One B-rep face of a CAD part: STEP entity #139.
In plain terms, the planar face has unit normal (-1, 0, 0).
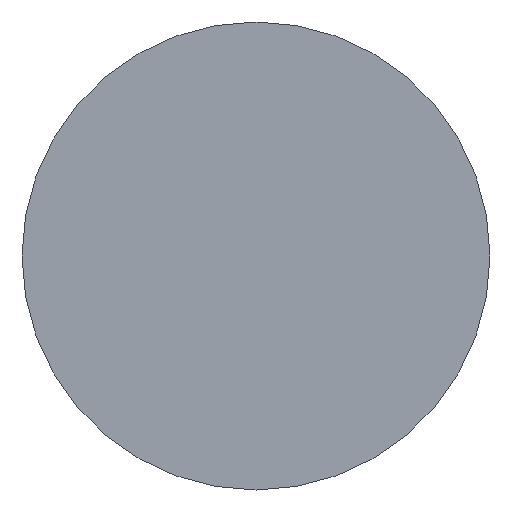
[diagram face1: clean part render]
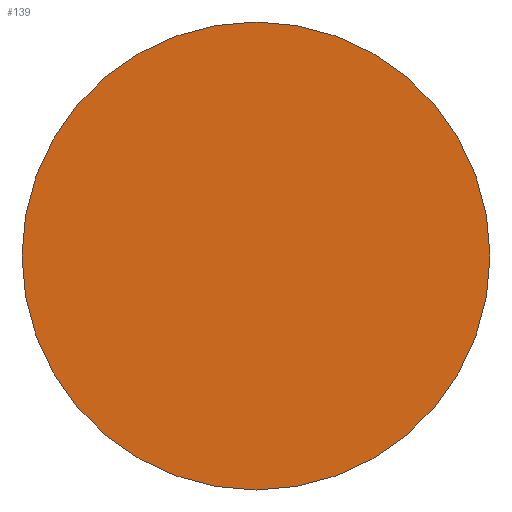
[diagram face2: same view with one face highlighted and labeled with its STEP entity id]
Its self-contained STEP definition (entity closure, numbers rounded to 3 decimals):
#31 = CYLINDRICAL_SURFACE('',#32,1.9);
#32 = AXIS2_PLACEMENT_3D('',#33,#34,#35);
#33 = CARTESIAN_POINT('',(-43.1,28.,239.));
#34 = DIRECTION('',(1.,0.,0.));
#35 = DIRECTION('',(0.,0.,1.));
#56 = VERTEX_POINT('',#57);
#57 = CARTESIAN_POINT('',(-43.1,28.,237.1));
#77 = EDGE_CURVE('',#56,#56,#78,.T.);
#78 = SURFACE_CURVE('',#79,(#84,#91),.PCURVE_S1.);
#79 = CIRCLE('',#80,1.9);
#80 = AXIS2_PLACEMENT_3D('',#81,#82,#83);
#81 = CARTESIAN_POINT('',(-43.1,28.,239.));
#82 = DIRECTION('',(1.,-0.,0.));
#83 = DIRECTION('',(0.,0.,-1.));
#84 = PCURVE('',#31,#85);
#85 = DEFINITIONAL_REPRESENTATION('',(#86),#90);
#86 = LINE('',#87,#88);
#87 = CARTESIAN_POINT('',(3.142,0.));
#88 = VECTOR('',#89,1.);
#89 = DIRECTION('',(1.,0.));
#90 = ( GEOMETRIC_REPRESENTATION_CONTEXT(2) 
PARAMETRIC_REPRESENTATION_CONTEXT() REPRESENTATION_CONTEXT('2D SPACE',''
  ) );
#91 = PCURVE('',#92,#97);
#92 = PLANE('',#93);
#93 = AXIS2_PLACEMENT_3D('',#94,#95,#96);
#94 = CARTESIAN_POINT('',(-43.1,28.,239.));
#95 = DIRECTION('',(1.,0.,0.));
#96 = DIRECTION('',(0.,0.,1.));
#97 = DEFINITIONAL_REPRESENTATION('',(#98),#102);
#98 = CIRCLE('',#99,1.9);
#99 = AXIS2_PLACEMENT_2D('',#100,#101);
#100 = CARTESIAN_POINT('',(0.,0.));
#101 = DIRECTION('',(-1.,0.));
#102 = ( GEOMETRIC_REPRESENTATION_CONTEXT(2) 
PARAMETRIC_REPRESENTATION_CONTEXT() REPRESENTATION_CONTEXT('2D SPACE',''
  ) );
#139 = ADVANCED_FACE('',(#140),#92,.F.);
#140 = FACE_BOUND('',#141,.T.);
#141 = EDGE_LOOP('',(#142));
#142 = ORIENTED_EDGE('',*,*,#77,.F.);
